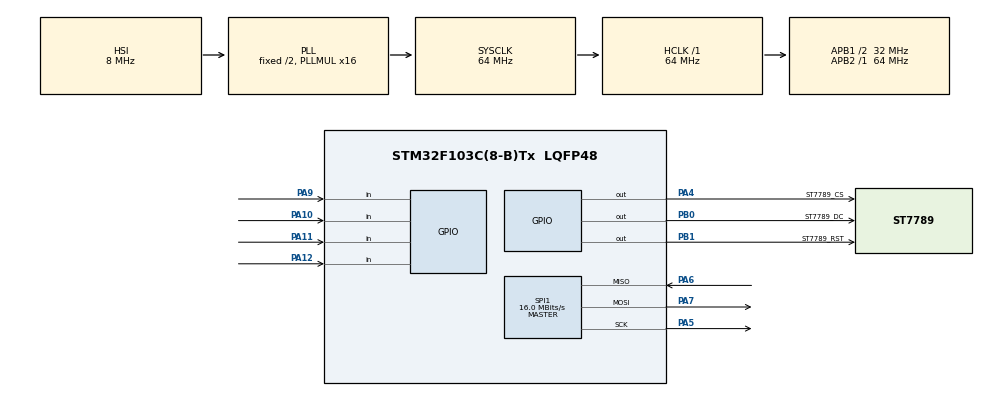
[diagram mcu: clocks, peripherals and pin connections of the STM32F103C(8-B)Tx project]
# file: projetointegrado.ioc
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Mcu.Family=STM32F1
Mcu.Name=STM32F103C(8-B)Tx
Mcu.Package=LQFP48
NVIC.PriorityGroup=NVIC_PRIORITYGROUP_4
PA10.GPIO_PuPd=GPIO_PULLUP
PA10.Signal=GPIO_Input
PA11.GPIO_PuPd=GPIO_PULLUP
PA11.Signal=GPIO_Input
PA12.GPIO_PuPd=GPIO_PULLUP
PA12.Signal=GPIO_Input
PA13.Mode=Serial_Wire
PA13.Signal=SYS_JTMS-SWDIO
PA14.Mode=Serial_Wire
PA14.Signal=SYS_JTCK-SWCLK
PA4.GPIO_Label=ST7789_CS
PA4.Signal=GPIO_Output
PA5.Mode=Full_Duplex_Master
PA5.Signal=SPI1_SCK
PA6.Mode=Full_Duplex_Master
PA6.Signal=SPI1_MISO
PA7.Mode=Full_Duplex_Master
PA7.Signal=SPI1_MOSI
PA9.GPIO_PuPd=GPIO_PULLUP
PA9.Signal=GPIO_Input
PB0.GPIO_Label=ST7789_DC
PB0.Signal=GPIO_Output
PB1.GPIO_Label=ST7789_RST
PB1.Signal=GPIO_Output
ProjectManager.HeapSize=0x200
ProjectManager.StackSize=0x400
ProjectManager.TargetToolchain=STM32CubeIDE
RCC.AHBFreq_Value=64000000
RCC.APB1CLKDivider=RCC_HCLK_DIV2
RCC.APB1Freq_Value=32000000
RCC.APB1TimFreq_Value=64000000
RCC.APB2Freq_Value=64000000
RCC.APB2TimFreq_Value=64000000
RCC.HCLKFreq_Value=64000000
RCC.PLLMUL=RCC_PLL_MUL16
RCC.SYSCLKFreq_VALUE=64000000
RCC.SYSCLKSource=RCC_SYSCLKSOURCE_PLLCLK
RCC.USBFreq_Value=64000000
SPI1.BaudRatePrescaler=SPI_BAUDRATEPRESCALER_4
SPI1.CLKPolarity=SPI_POLARITY_HIGH
SPI1.CalculateBaudRate=16.0 MBits/s
SPI1.Direction=SPI_DIRECTION_2LINES
SPI1.Mode=SPI_MODE_MASTER
SPI1.VirtualType=VM_MASTER
board=custom

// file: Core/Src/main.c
/* USER CODE BEGIN Header */
/**
  ******************************************************************************
  * @file           : main.c
  * @brief          : Main program body
  ******************************************************************************
  * @attention
  *
  * <h2><center>&copy; Copyright (c) 2025 STMicroelectronics.
  * All rights reserved.</center></h2>
  *
  * This software component is licensed by ST under BSD 3-Clause license,
  * the "License"; You may not use this file except in compliance with the
  * License. You may obtain a copy of the License at:
  *                        opensource.org/licenses/BSD-3-Clause
  *
  ******************************************************************************
  */
/* USER CODE END Header */
#include "main.h"
/* USER CODE BEGIN Includes */
#include "st7789\st7789.h"
#include <stdio.h>
#include <stdbool.h>
#include <stdlib.h>

/* USER CODE END Includes */

SPI_HandleTypeDef hspi1;

#define size 4
#define colorBG WHITE
#define colorCard BLACK
char tabuleiro[size][size];
int entradaCima = 0;
int entradaEsquerda = 0;
int entradaBaixo =0;
int entradaDireita =0;
int cursorX = 0;
int cursorY = 0;
int carta1X = 0;
int carta2X = 0;
int carta1Y = 0;
int carta2Y = 0;
int linha = 0;
int coluna = 0;
int verifica = 0;
bool revelado [size][size];
int selecionadas = 0;
int cor[size][size];
char cartas[size][size];
int tentativa = 0;
int tentativa2;
int recorde = 0;
char pt[15];
char rc[15];

#define CARTAPI_HEIGHT 30
#define CARTAPI_WIDTH 25

// array size is 2250
#define CARTAPI_HEIGHT 30
#define CARTAPI_WIDTH 25

// array size is 2250
#define CARTAPI_HEIGHT 30
#define CARTAPI_WIDTH 25

// array size is 1500
static const uint16_t cartaPI[][25*30/2]  = {
  0x0000, 0x0000, 0x0000, 0x0000, 0x0000, 0x0000, 0x0000, 0x0000, 0x0000, 0x0000, 0x0000, 0x0000, 0x0000, 0x0000, 0x0000, 0x0000, 0x0000, 0x0000, 0x0000, 0x0000, 0x0000, 0x0000, 0x0000, 0x0000, 0x0000,
  0x0000, 0xdd9e, 0xdd9e, 0xdd9e, 0xdd9e, 0xdd9e, 0xdd9e, 0xdd9e, 0xdd9e, 0xdd9e, 0xdd9e, 0xdd9e, 0xdd9e, 0xdd9e, 0xdd9e, 0xdd9e, 0xdd9e, 0xdd9e, 0xdd9e, 0xdd9e, 0xdd9e, 0xdd9e, 0xdd9e, 0xdd9e, 0x0000,
  0x0000, 0xdd9e, 0xffff, 0xffff, 0xffff, 0xffff, 0xffff, 0xffff, 0xffff, 0xffff, 0xffff, 0xffff, 0xffff, 0xffff, 0xffff, 0xffff, 0xffff, 0xffff, 0xffff, 0xffff, 0xffff, 0xffff, 0xffff, 0xdd9e, 0x0000,
  0x0000, 0xdd9e, 0xffff, 0xffff, 0xffff, 0xffff, 0xffff, 0xffff, 0xffff, 0xffff, 0xffff, 0xffff, 0xffff, 0xffff, 0xffff, 0xffff, 0xffff, 0xffff, 0xffff, 0xffff, 0xffff, 0xffff, 0xffff, 0xdd9e, 0x0000,
  0x0000, 0xdd9e, 0xffff, 0xffff, 0xdd9e, 0xdd9e, 0x1d05, 0xdd9e, 0xdd9e, 0x1d05, 0xdd9e, 0xdd9e, 0x1d05, 0xdd9e, 0xdd9e, 0x1d05, 0xdd9e, 0xdd9e, 0x1d05, 0xdd9e, 0xdd9e, 0xffff, 0xffff, 0xdd9e, 0x0000,
  0x0000, 0xdd9e, 0xffff, 0xffff, 0xdd9e, 0x1d05, 0xdd9e, 0x1d05, 0xdd9e, 0xdd9e, 0xdd9e, 0x1d05, 0xdd9e, 0x1d05, 0xdd9e, 0xdd9e, 0xdd9e, 0x1d05, 0xdd9e, 0x1d05, 0xdd9e, 0xffff, 0xffff, 0xdd9e, 0x0000,
  0x0000, 0xdd9e, 0xffff, 0xffff, 0x1d05, 0xdd9e, 0xdd9e, 0xdd9e, 0x1d05, 0xdd9e, 0x1d05, 0xdd9e, 0xdd9e, 0xdd9e, 0x1d05, 0xdd9e, 0x1d05, 0xdd9e, 0xdd9e, 0xdd9e, 0x1d05, 0xffff, 0xffff, 0xdd9e, 0x0000,
  0x0000, 0xdd9e, 0xffff, 0xffff, 0xdd9e, 0x1d05, 0xdd9e, 0x1d05, 0xdd9e, 0xdd9e, 0xdd9e, 0x1d05, 0xdd9e, 0x1d05, 0xdd9e, 0xdd9e, 0xdd9e, 0x1d05, 0xdd9e, 0x1d05, 0xdd9e, 0xffff, 0xffff, 0xdd9e, 0x0000,
  0x0000, 0xdd9e, 0xffff, 0xffff, 0xdd9e, 0xdd9e, 0x1d05, 0xdd9e, 0xdd9e, 0x1d05, 0xdd9e, 0xdd9e, 0x1d05, 0xdd9e, 0xdd9e, 0x1d05, 0xdd9e, 0xdd9e, 0x1d05, 0xdd9e, 0xdd9e, 0xffff, 0xffff, 0xdd9e, 0x0000,
  0x0000, 0xdd9e, 0xffff, 0xffff, 0xdd9e, 0x1d05, 0xdd9e, 0x1d05, 0xdd9e, 0xdd9e, 0xdd9e, 0x1d05, 0xdd9e, 0x1d05, 0xdd9e, 0xdd9e, 0xdd9e, 0x1d05, 0xdd9e, 0x1d05, 0xdd9e, 0xffff, 0xffff, 0xdd9e, 0x0000,
  0x0000, 0xdd9e, 0xffff, 0xffff, 0x1d05, 0xdd9e, 0xdd9e, 0xdd9e, 0x1d05, 0xdd9e, 0x1d05, 0xdd9e, 0xdd9e, 0xdd9e, 0x1d05, 0xdd9e, 0x1d05, 0xdd9e, 0xdd9e, 0xdd9e, 0x1d05, 0xffff, 0xffff, 0xdd9e, 0x0000,
  0x0000, 0xdd9e, 0xffff, 0xffff, 0xdd9e, 0x1d05, 0xdd9e, 0x1d05, 0xdd9e, 0xdd9e, 0xdd9e, 0x1d05, 0xdd9e, 0x1d05, 0xdd9e, 0xdd9e, 0xdd9e, 0x1d05, 0xdd9e, 0x1d05, 0xdd9e, 0xffff, 0xffff, 0xdd9e, 0x0000,
  0x0000, 0xdd9e, 0xffff, 0xffff, 0xdd9e, 0xdd9e, 0x1d05, 0xdd9e, 0xdd9e, 0x1d05, 0xdd9e, 0xdd9e, 0x1d05, 0xdd9e, 0xdd9e, 0x1d05, 0xdd9e, 0xdd9e, 0x1d05, 0xdd9e, 0xdd9e, 0xffff, 0xffff, 0xdd9e, 0x0000,
  0x0000, 0xdd9e, 0xffff, 0xffff, 0xdd9e, 0x1d05, 0xdd9e, 0x1d05, 0xdd9e, 0xdd9e, 0xdd9e, 0x1d05, 0xdd9e, 0x1d05, 0xdd9e, 0xdd9e, 0xdd9e, 0x1d05, 0xdd9e, 0x1d05, 0xdd9e, 0xffff, 0xffff, 0xdd9e, 0x0000,
  0x0000, 0xdd9e, 0xffff, 0xffff, 0x1d05, 0xdd9e, 0xdd9e, 0xdd9e, 0x1d05, 0xdd9e, 0x1d05, 0xdd9e, 0xdd9e, 0xdd9e, 0x1d05, 0xdd9e, 0x1d05, 0xdd9e, 0xdd9e, 0xdd9e, 0x1d05, 0xffff, 0xffff, 0xdd9e, 0x0000,
  0x0000, 0xdd9e, 0xffff, 0xffff, 0x1d05, 0xdd9e, 0xdd9e, 0xdd9e, 0x1d05, 0xdd9e, 0x1d05, 0xdd9e, 0xdd9e, 0xdd9e, 0x1d05, 0xdd9e, 0x1d05, 0xdd9e, 0xdd9e, 0xdd9e, 0x1d05, 0xffff, 0xffff, 0xdd9e, 0x0000,
  0x0000, 0xdd9e, 0xffff, 0xffff, 0xdd9e, 0x1d05, 0xdd9e, 0x1d05, 0xdd9e, 0xdd9e, 0xdd9e, 0x1d05, 0xdd9e, 0x1d05, 0xdd9e, 0xdd9e, 0xdd9e, 0x1d05, 0xdd9e, 0x1d05, 0xdd9e, 0xffff, 0xffff, 0xdd9e, 0x0000,
  0x0000, 0xdd9e, 0xffff, 0xffff, 0xdd9e, 0xdd9e, 0x1d05, 0xdd9e, 0xdd9e, 0x1d05, 0xdd9e, 0xdd9e, 0x1d05, 0xdd9e, 0xdd9e, 0x1d05, 0xdd9e, 0xdd9e, 0x1d05, 0xdd9e, 0xdd9e, 0xffff, 0xffff, 0xdd9e, 0x0000,
  0x0000, 0xdd9e, 0xffff, 0xffff, 0xdd9e, 0x1d05, 0xdd9e, 0x1d05, 0xdd9e, 0xdd9e, 0xdd9e, 0x1d05, 0xdd9e, 0x1d05, 0xdd9e, 0xdd9e, 0xdd9e, 0x1d05, 0xdd9e, 0x1d05, 0xdd9e, 0xffff, 0xffff, 0xdd9e, 0x0000,
  0x0000, 0xdd9e, 0xffff, 0xffff, 0x1d05, 0xdd9e, 0xdd9e, 0xdd9e, 0x1d05, 0xdd9e, 0x1d05, 0xdd9e, 0xdd9e, 0xdd9e, 0x1d05, 0xdd9e, 0x1d05, 0xdd9e, 0xdd9e, 0xdd9e, 0x1d05, 0xffff, 0xffff, 0xdd9e, 0x0000,
  0x0000, 0xdd9e, 0xffff, 0xffff, 0xdd9e, 0x1d05, 0xdd9e, 0x1d05, 0xdd9e, 0xdd9e, 0xdd9e, 0x1d05, 0xdd9e, 0x1d05, 0xdd9e, 0xdd9e, 0xdd9e, 0x1d05, 0xdd9e, 0x1d05, 0xdd9e, 0xffff, 0xffff, 0xdd9e, 0x0000,
  0x0000, 0xdd9e, 0xffff, 0xffff, 0xdd9e, 0xdd9e, 0x1d05, 0xdd9e, 0xdd9e, 0x1d05, 0xdd9e, 0xdd9e, 0x1d05, 0xdd9e, 0xdd9e, 0x1d05, 0xdd9e, 0xdd9e, 0x1d05, 0xdd9e, 0xdd9e, 0xffff, 0xffff, 0xdd9e, 0x0000,
  0x0000, 0xdd9e, 0xffff, 0xffff, 0xdd9e, 0x1d05, 0xdd9e, 0x1d05, 0xdd9e, 0xdd9e, 0xdd9e, 0x1d05, 0xdd9e, 0x1d05, 0xdd9e, 0xdd9e, 0xdd9e, 0x1d05, 0xdd9e, 0x1d05, 0xdd9e, 0xffff, 0xffff, 0xdd9e, 0x0000,
  0x0000, 0xdd9e, 0xffff, 0xffff, 0x1d05, 0xdd9e, 0xdd9e, 0xdd9e, 0x1d05, 0xdd9e, 0x1d05, 0xdd9e, 0xdd9e, 0xdd9e, 0x1d05, 0xdd9e, 0x1d05, 0xdd9e, 0xdd9e, 0xdd9e, 0x1d05, 0xffff, 0xffff, 0xdd9e, 0x0000,
  0x0000, 0xdd9e, 0xffff, 0xffff, 0xdd9e, 0x1d05, 0xdd9e, 0x1d05, 0xdd9e, 0xdd9e, 0xdd9e, 0x1d05, 0xdd9e, 0x1d05, 0xdd9e, 0xdd9e, 0xdd9e, 0x1d05, 0xdd9e, 0x1d05, 0xdd9e, 0xffff, 0xffff, 0xdd9e, 0x0000,
  0x0000, 0xdd9e, 0xffff, 0xffff, 0xdd9e, 0xdd9e, 0x1d05, 0xdd9e, 0xdd9e, 0x1d05, 0xdd9e, 0xdd9e, 0x1d05, 0xdd9e, 0xdd9e, 0x1d05, 0xdd9e, 0xdd9e, 0x1d05, 0xdd9e, 0xdd9e, 0xffff, 0xffff, 0xdd9e, 0x0000,
  0x0000, 0xdd9e, 0xffff, 0xffff, 0xffff, 0xffff, 0xffff, 0xffff, 0xffff, 0xffff, 0xffff, 0xffff, 0xffff, 0xffff, 0xffff, 0xffff, 0xffff, 0xffff, 0xffff, 0xffff, 0xffff, 0xffff, 0xffff, 0xdd9e, 0x0000,
  0x0000, 0xdd9e, 0xffff, 0xffff, 0xffff, 0xffff, 0xffff, 0xffff, 0xffff, 0xffff, 0xffff, 0xffff, 0xffff, 0xffff, 0xffff, 0xffff, 0xffff, 0xffff, 0xffff, 0xffff, 0xffff, 0xffff, 0xffff, 0xdd9e, 0x0000,
  0x0000, 0xdd9e, 0xdd9e, 0xdd9e, 0xdd9e, 0xdd9e, 0xdd9e, 0xdd9e, 0xdd9e, 0xdd9e, 0xdd9e, 0xdd9e, 0xdd9e, 0xdd9e, 0xdd9e, 0xdd9e, 0xdd9e, 0xdd9e, 0xdd9e, 0xdd9e, 0xdd9e, 0xdd9e, 0xdd9e, 0xdd9e, 0x0000,
  0x0000, 0x0000, 0x0000, 0x0000, 0x0000, 0x0000, 0x0000, 0x0000, 0x0000, 0x0000, 0x0000, 0x0000, 0x0000, 0x0000, 0x0000, 0x0000, 0x0000, 0x0000, 0x0000, 0x0000, 0x0000, 0x0000, 0x0000, 0x0000, 0x0000
};
#define NEW_PISKEL_1_PNG_HEIGHT 45
#define NEW_PISKEL_1_PNG_WIDTH 31

// array size is 2790
static const int16_t New_Piskel_1_png[][31*45/2]  = {
  0x0000, 0x0000, 0x0000, 0x0000, 0x0000, 0x0000, 0x0000, 0x0000, 0x0000, 0x0000, 0x0000, 0x0000, 0x0000, 0x0000, 0x0000, 0x0000, 0x0000, 0x0000, 0x0000, 0x0000, 0x0000, 0x0000, 0x0000, 0x0000, 0x0000, 0x0000, 0x0000, 0x0000, 0x0000, 0x0000, 0x0000,
  0x0000, 0x5f7c, 0x5f7c, 0x5f7c, 0x5f7c, 0x5f7c, 0x5f7c, 0x5f7c, 0x5f7c, 0x5f7c, 0x5f7c, 0x5f7c, 0x5f7c, 0x5f7c, 0x5f7c, 0x5f7c, 0x5f7c, 0x5f7c, 0x5f7c, 0x5f7c, 0x5f7c, 0x5f7c, 0x5f7c, 0x5f7c, 0x5f7c, 0x5f7c, 0x5f7c, 0x5f7c, 0x5f7c, 0x5f7c, 0x0000,
  0x0000, 0x5f7c, 0xffde, 0xffde, 0xffde, 0xffde, 0xffde, 0xffde, 0xffde, 0xffde, 0xffde, 0xffde, 0xffde, 0xffde, 0xffde, 0xffde, 0xffde, 0xffde, 0xffde, 0xffde, 0xffde, 0xffde, 0xffde, 0xffde, 0xffde, 0xffde, 0xffde, 0xffde, 0xffde, 0x5f7c, 0x0000,
  0x0000, 0x5f7c, 0xffde, 0xffde, 0xffde, 0xffde, 0xffde, 0xffde, 0xffde, 0xffde, 0xffde, 0xffde, 0xffde, 0xffde, 0xffde, 0xffde, 0xffde, 0xffde, 0xffde, 0xffde, 0xffde, 0xffde, 0xffde, 0xffde, 0xffde, 0xffde, 0xffde, 0xffde, 0xffde, 0x5f7c, 0x0000,
  0x0000, 0x5f7c, 0xffde, 0xffde, 0x5f7c, 0x5f7c, 0x5f7c, 0xdf21, 0x5f7c, 0x5f7c, 0x5f7c, 0x5f7c, 0x5f7c, 0x5f7c, 0x5f7c, 0xdf21, 0x5f7c, 0x5f7c, 0x5f7c, 0x5f7c, 0x5f7c, 0x5f7c, 0x5f7c, 0xdf21, 0x5f7c, 0x5f7c, 0x5f7c, 0xffde, 0xffde, 0x5f7c, 0x0000,
  0x0000, 0x5f7c, 0xffde, 0xffde, 0x5f7c, 0x5f7c, 0xdf21, 0x5f7c, 0xdf21, 0x5f7c, 0x5f7c, 0x5f7c, 0x5f7c, 0x5f7c, 0xdf21, 0x5f7c, 0xdf21, 0x5f7c, 0x5f7c, 0x5f7c, 0x5f7c, 0x5f7c, 0xdf21, 0x5f7c, 0xdf21, 0x5f7c, 0x5f7c, 0xffde, 0xffde, 0x5f7c, 0x0000,
  0x0000, 0x5f7c, 0xffde, 0xffde, 0x5f7c, 0xdf21, 0x5f7c, 0x5f7c, 0x5f7c, 0xdf21, 0x5f7c, 0x5f7c, 0x5f7c, 0xdf21, 0x5f7c, 0x5f7c, 0x5f7c, 0xdf21, 0x5f7c, 0x5f7c, 0x5f7c, 0xdf21, 0x5f7c, 0x5f7c, 0x5f7c, 0xdf21, 0x5f7c, 0xffde, 0xffde, 0x5f7c, 0x0000,
  0x0000, 0x5f7c, 0xffde, 0xffde, 0xdf21, 0x5f7c, 0x5f7c, 0x5f7c, 0x5f7c, 0x5f7c, 0xdf21, 0x5f7c, 0xdf21, 0x5f7c, 0x5f7c, 0x5f7c, 0x5f7c, 0x5f7c, 0xdf21, 0x5f7c, 0xdf21, 0x5f7c, 0x5f7c, 0x5f7c, 0x5f7c, 0x5f7c, 0xdf21, 0xffde, 0xffde, 0x5f7c, 0x0000,
  0x0000, 0x5f7c, 0xffde, 0xffde, 0x5f7c, 0xdf21, 0x5f7c, 0x5f7c, 0x5f7c, 0xdf21, 0x5f7c, 0x5f7c, 0x5f7c, 0xdf21, 0x5f7c, 0x5f7c, 0x5f7c, 0xdf21, 0x5f7c, 0x5f7c, 0x5f7c, 0xdf21, 0x5f7c, 0x5f7c, 0x5f7c, 0xdf21, 0x5f7c, 0xffde, 0xffde, 0x5f7c, 0x0000,
  0x0000, 0x5f7c, 0xffde, 0xffde, 0x5f7c, 0x5f7c, 0xdf21, 0x5f7c, 0xdf21, 0x5f7c, 0x5f7c, 0x5f7c, 0x5f7c, 0x5f7c, 0xdf21, 0x5f7c, 0xdf21, 0x5f7c, 0x5f7c, 0x5f7c, 0x5f7c, 0x5f7c, 0xdf21, 0x5f7c, 0xdf21, 0x5f7c, 0x5f7c, 0xffde, 0xffde, 0x5f7c, 0x0000,
  0x0000, 0x5f7c, 0xffde, 0xffde, 0x5f7c, 0x5f7c, 0x5f7c, 0xdf21, 0x5f7c, 0x5f7c, 0x5f7c, 0x5f7c, 0x5f7c, 0x5f7c, 0x5f7c, 0xdf21, 0x5f7c, 0x5f7c, 0x5f7c, 0x5f7c, 0x5f7c, 0x5f7c, 0x5f7c, 0xdf21, 0x5f7c, 0x5f7c, 0x5f7c, 0xffde, 0xffde, 0x5f7c, 0x0000,
  0x0000, 0x5f7c, 0xffde, 0xffde, 0x5f7c, 0x5f7c, 0xdf21, 0x5f7c, 0xdf21, 0x5f7c, 0x5f7c, 0x5f7c, 0x5f7c, 0x5f7c, 0xdf21, 0x5f7c, 0xdf21, 0x5f7c, 0x5f7c, 0x5f7c, 0x5f7c, 0x5f7c, 0xdf21, 0x5f7c, 0xdf21, 0x5f7c, 0x5f7c, 0xffde, 0xffde, 0x5f7c, 0x0000,
  0x0000, 0x5f7c, 0xffde, 0xffde, 0x5f7c, 0xdf21, 0x5f7c, 0x5f7c, 0x5f7c, 0xdf21, 0x5f7c, 0x5f7c, 0x5f7c, 0xdf21, 0x5f7c, 0x5f7c, 0x5f7c, 0xdf21, 0x5f7c, 0x5f7c, 0x5f7c, 0xdf21, 0x5f7c, 0x5f7c, 0x5f7c, 0xdf21, 0x5f7c, 0xffde, 0xffde, 0x5f7c, 0x0000,
  0x0000, 0x5f7c, 0xffde, 0xffde, 0xdf21, 0x5f7c, 0x5f7c, 0x5f7c, 0x5f7c, 0x5f7c, 0xdf21, 0x5f7c, 0xdf21, 0x5f7c, 0x5f7c, 0x5f7c, 0x5f7c, 0x5f7c, 0xdf21, 0x5f7c, 0xdf21, 0x5f7c, 0x5f7c, 0x5f7c, 0x5f7c, 0x5f7c, 0xdf21, 0xffde, 0xffde, 0x5f7c, 0x0000,
  0x0000, 0x5f7c, 0xffde, 0xffde, 0x5f7c, 0xdf21, 0x5f7c, 0x5f7c, 0x5f7c, 0xdf21, 0x5f7c, 0x5f7c, 0x5f7c, 0xdf21, 0x5f7c, 0x5f7c, 0x5f7c, 0xdf21, 0x5f7c, 0x5f7c, 0x5f7c, 0xdf21, 0x5f7c, 0x5f7c, 0x5f7c, 0xdf21, 0x5f7c, 0xffde, 0xffde, 0x5f7c, 0x0000,
  0x0000, 0x5f7c, 0xffde, 0xffde, 0x5f7c, 0x5f7c, 0xdf21, 0x5f7c, 0xdf21, 0x5f7c, 0x5f7c, 0x5f7c, 0x5f7c, 0x5f7c, 0xdf21, 0x5f7c, 0xdf21, 0x5f7c, 0x5f7c, 0x5f7c, 0x5f7c, 0x5f7c, 0xdf21, 0x5f7c, 0xdf21, 0x5f7c, 0x5f7c, 0xffde, 0xffde, 0x5f7c, 0x0000,
  0x0000, 0x5f7c, 0xffde, 0xffde, 0x5f7c, 0x5f7c, 0x5f7c, 0xdf21, 0x5f7c, 0x5f7c, 0x5f7c, 0x5f7c, 0x5f7c, 0x5f7c, 0x5f7c, 0xdf21, 0x5f7c, 0x5f7c, 0x5f7c, 0x5f7c, 0x5f7c, 0x5f7c, 0x5f7c, 0xdf21, 0x5f7c, 0x5f7c, 0x5f7c, 0xffde, 0xffde, 0x5f7c, 0x0000,
  0x0000, 0x5f7c, 0xffde, 0xffde, 0x5f7c, 0x5f7c, 0xdf21, 0x5f7c, 0xdf21, 0x5f7c, 0x5f7c, 0x5f7c, 0x5f7c, 0x5f7c, 0xdf21, 0x5f7c, 0xdf21, 0x5f7c, 0x5f7c, 0x5f7c, 0x5f7c, 0x5f7c, 0xdf21, 0x5f7c, 0xdf21, 0x5f7c, 0x5f7c, 0xffde, 0xffde, 0x5f7c, 0x0000,
  0x0000, 0x5f7c, 0xffde, 0xffde, 0x5f7c, 0xdf21, 0x5f7c, 0x5f7c, 0x5f7c, 0xdf21, 0x5f7c, 0x5f7c, 0x5f7c, 0xdf21, 0x5f7c, 0x5f7c, 0x5f7c, 0xdf21, 0x5f7c, 0x5f7c, 0x5f7c, 0xdf21, 0x5f7c, 0x5f7c, 0x5f7c, 0xdf21, 0x5f7c, 0xffde, 0xffde, 0x5f7c, 0x0000,
  0x0000, 0x5f7c, 0xffde, 0xffde, 0xdf21, 0x5f7c, 0x5f7c, 0x5f7c, 0x5f7c, 0x5f7c, 0xdf21, 0x5f7c, 0xdf21, 0x5f7c, 0x5f7c, 0x5f7c, 0x5f7c, 0x5f7c, 0xdf21, 0x5f7c, 0xdf21, 0x5f7c, 0x5f7c, 0x5f7c, 0x5f7c, 0x5f7c, 0xdf21, 0xffde, 0xffde, 0x5f7c, 0x0000,
  0x0000, 0x5f7c, 0xffde, 0xffde, 0x5f7c, 0xdf21, 0x5f7c, 0x5f7c, 0x5f7c, 0xdf21, 0x5f7c, 0x5f7c, 0x5f7c, 0xdf21, 0x5f7c, 0x5f7c, 0x5f7c, 0xdf21, 0x5f7c, 0x5f7c, 0x5f7c, 0xdf21, 0x5f7c, 0x5f7c, 0x5f7c, 0xdf21, 0x5f7c, 0xffde, 0xffde, 0x5f7c, 0x0000,
  0x0000, 0x5f7c, 0xffde, 0xffde, 0x5f7c, 0x5f7c, 0xdf21, 0x5f7c, 0xdf21, 0x5f7c, 0x5f7c, 0x5f7c, 0x5f7c, 0x5f7c, 0xdf21, 0x5f7c, 0xdf21, 0x5f7c, 0x5f7c, 0x5f7c, 0x5f7c, 0x5f7c, 0xdf21, 0x5f7c, 0xdf21, 0x5f7c, 0x5f7c, 0xffde, 0xffde, 0x5f7c, 0x0000,
  0x0000, 0x5f7c, 0xffde, 0xffde, 0x5f7c, 0x5f7c, 0x5f7c, 0xdf21, 0x5f7c, 0x5f7c, 0x5f7c, 0x5f7c, 0x5f7c, 0x5f7c, 0x5f7c, 0xdf21, 0x5f7c, 0x5f7c, 0x5f7c, 0x5f7c, 0x5f7c, 0x5f7c, 0x5f7c, 0xdf21, 0x5f7c, 0x5f7c, 0x5f7c, 0xffde, 0xffde, 0x5f7c, 0x0000,
  0x0000, 0x5f7c, 0xffde, 0xffde, 0x5f7c, 0x5f7c, 0xdf21, 0x5f7c, 0xdf21, 0x5f7c, 0x5f7c, 0x5f7c, 0x5f7c, 0x5f7c, 0xdf21, 0x5f7c, 0xdf21, 0x5f7c, 0x5f7c, 0x5f7c, 0x5f7c, 0x5f7c, 0xdf21, 0x5f7c, 0xdf21, 0x5f7c, 0x5f7c, 0xffde, 0xffde, 0x5f7c, 0x0000,
  0x0000, 0x5f7c, 0xffde, 0xffde, 0x5f7c, 0xdf21, 0x5f7c, 0x5f7c, 0x5f7c, 0xdf21, 0x5f7c, 0x5f7c, 0x5f7c, 0xdf21, 0x5f7c, 0x5f7c, 0x5f7c, 0xdf21, 0x5f7c, 0x5f7c, 0x5f7c, 0xdf21, 0x5f7c, 0x5f7c, 0x5f7c, 0xdf21, 0x5f7c, 0xffde, 0xffde, 0x5f7c, 0x0000,
  0x0000, 0x5f7c, 0xffde, 0xffde, 0xdf21, 0x5f7c, 0x5f7c, 0x5f7c, 0x5f7c, 0x5f7c, 0xdf21, 0x5f7c, 0xdf21, 0x5f7c, 0x5f7c, 0x5f7c, 0x5f7c, 0x5f7c, 0xdf21, 0x5f7c, 0xdf21, 0x5f7c, 0x5f7c, 0x5f7c, 0x5f7c, 0x5f7c, 0xdf21, 0xffde, 0xffde, 0x5f7c, 0x0000,
  0x0000, 0x5f7c, 0xffde, 0xffde, 0x5f7c, 0xdf21, 0x5f7c, 0x5f7c, 0x5f7c, 0xdf21, 0x5f7c, 0x5f7c, 0x5f7c, 0xdf21, 0x5f7c, 0x5f7c, 0x5f7c, 0xdf21, 0x5f7c, 0x5f7c, 0x5f7c, 0xdf21, 0x5f7c, 0x5f7c, 0x5f7c, 0xdf21, 0x5f7c, 0xffde, 0xffde, 0x5f7c, 0x0000,
  0x0000, 0x5f7c, 0xffde, 0xffde, 0x5f7c, 0x5f7c, 0xdf21, 0x5f7c, 0xdf21, 0x5f7c, 0x5f7c, 0x5f7c, 0x5f7c, 0x5f7c, 0xdf21, 0x5f7c, 0xdf21, 0x5f7c, 0x5f7c, 0x5f7c, 0x5f7c, 0x5f7c, 0xdf21, 0x5f7c, 0xdf21, 0x5f7c, 0x5f7c, 0xffde, 0xffde, 0x5f7c, 0x0000,
  0x0000, 0x5f7c, 0xffde, 0xffde, 0x5f7c, 0x5f7c, 0x5f7c, 0xdf21, 0x5f7c, 0x5f7c, 0x5f7c, 0x5f7c, 0x5f7c, 0x5f7c, 0x5f7c, 0xdf21, 0x5f7c, 0x5f7c, 0x5f7c, 0x5f7c, 0x5f7c, 0x5f7c, 0x5f7c, 0xdf21, 0x5f7c, 0x5f7c, 0x5f7c, 0xffde, 0xffde, 0x5f7c, 0x0000,
  0x0000, 0x5f7c, 0xffde, 0xffde, 0x5f7c, 0x5f7c, 0xdf21, 0x5f7c, 0xdf21, 0x5f7c, 0x5f7c, 0x5f7c, 0x5f7c, 0x5f7c, 0xdf21, 0x5f7c, 0xdf21, 0x5f7c, 0x5f7c, 0x5f7c, 0x5f7c, 0x5f7c, 0xdf21, 0x5f7c, 0xdf21, 0x5f7c, 0x5f7c, 0xffde, 0xffde, 0x5f7c, 0x0000,
  0x0000, 0x5f7c, 0xffde, 0xffde, 0x5f7c, 0xdf21, 0x5f7c, 0x5f7c, 0x5f7c, 0xdf21, 0x5f7c, 0x5f7c, 0x5f7c, 0xdf21, 0x5f7c, 0x5f7c, 0x5f7c, 0xdf21, 0x5f7c, 0x5f7c, 0x5f7c, 0xdf21, 0x5f7c, 0x5f7c, 0x5f7c, 0xdf21, 0x5f7c, 0xffde, 0xffde, 0x5f7c, 0x0000,
  0x0000, 0x5f7c, 0xffde, 0xffde, 0xdf21, 0x5f7c, 0x5f7c, 0x5f7c, 0x5f7c, 0x5f7c, 0xdf21, 0x5f7c, 0xdf21, 0x5f7c, 0x5f7c, 0x5f7c, 0x5f7c, 0x5f7c, 0xdf21, 0x5f7c, 0xdf21, 0x5f7c, 0x5f7c, 0x5f7c, 0x5f7c, 0x5f7c, 0xdf21, 0xffde, 0xffde, 0x5f7c, 0x0000,
  0x0000, 0x5f7c, 0xffde, 0xffde, 0x5f7c, 0xdf21, 0x5f7c, 0x5f7c, 0x5f7c, 0xdf21, 0x5f7c, 0x5f7c, 0x5f7c, 0xdf21, 0x5f7c, 0x5f7c, 0x5f7c, 0xdf21, 0x5f7c, 0x5f7c, 0x5f7c, 0xdf21, 0x5f7c, 0x5f7c, 0x5f7c, 0xdf21, 0x5f7c, 0xffde, 0xffde, 0x5f7c, 0x0000,
  0x0000, 0x5f7c, 0xffde, 0xffde, 0x5f7c, 0x5f7c, 0xdf21, 0x5f7c, 0xdf21, 0x5f7c, 0x5f7c, 0x5f7c, 0x5f7c, 0x5f7c, 0xdf21, 0x5f7c, 0xdf21, 0x5f7c, 0x5f7c, 0x5f7c, 0x5f7c, 0x5f7c, 0xdf21, 0x5f7c, 0xdf21, 0x5f7c, 0x5f7c, 0xffde, 0xffde, 0x5f7c, 0x0000,
  0x0000, 0x5f7c, 0xffde, 0xffde, 0x5f7c, 0x5f7c, 0x5f7c, 0xdf21, 0x5f7c, 0x5f7c, 0x5f7c, 0x5f7c, 0x5f7c, 0x5f7c, 0x5f7c, 0xdf21, 0x5f7c, 0x5f7c, 0x5f7c, 0x5f7c, 0x5f7c, 0x5f7c, 0x5f7c, 0xdf21, 0x5f7c, 0x5f7c, 0x5f7c, 0xffde, 0xffde, 0x5f7c, 0x0000,
  0x0000, 0x5f7c, 0xffde, 0xffde, 0x5f7c, 0x5f7c, 0xdf21, 0x5f7c, 0xdf21, 0x5f7c, 0x5f7c, 0x5f7c, 0x5f7c, 0x5f7c, 0xdf21, 0x5f7c, 0xdf21, 0x5f7c, 0x5f7c, 0x5f7c, 0x5f7c, 0x5f7c, 0xdf21, 0x5f7c, 0xdf21, 0x5f7c, 0x5f7c, 0xffde, 0xffde, 0x5f7c, 0x0000,
  0x0000, 0x5f7c, 0xffde, 0xffde, 0x5f7c, 0xdf21, 0x5f7c, 0x5f7c, 0x5f7c, 0xdf21, 0x5f7c, 0x5f7c, 0x5f7c, 0xdf21, 0x5f7c, 0x5f7c, 0x5f7c, 0xdf21, 0x5f7c, 0x5f7c, 0x5f7c, 0xdf21, 0x5f7c, 0x5f7c, 0x5f7c, 0xdf21, 0x5f7c, 0xffde, 0xffde, 0x5f7c, 0x0000,
  0x0000, 0x5f7c, 0xffde, 0xffde, 0xdf21, 0x5f7c, 0x5f7c, 0x5f7c, 0x5f7c, 0x5f7c, 0xdf21, 0x5f7c, 0xdf21, 0x5f7c, 0x5f7c, 0x5f7c, 0x5f7c, 0x5f7c, 0xdf21, 0x5f7c, 0xdf21, 0x5f7c, 0x5f7c, 0x5f7c, 0x5f7c, 0x5f7c, 0xdf21, 0xffde, 0xffde, 0x5f7c, 0x0000,
  0x0000, 0x5f7c, 0xffde, 0xffde, 0x5f7c, 0xdf21, 0x5f7c, 0x5f7c, 0x5f7c, 0xdf21, 0x5f7c, 0x5f7c, 0x5f7c, 0xdf21, 0x5f7c, 0x5f7c, 0x5f7c, 0xdf21, 0x5f7c, 0x5f7c, 0x5f7c, 0xdf21, 0x5f7c, 0x5f7c, 0x5f7c, 0xdf21, 0x5f7c, 0xffde, 0xffde, 0x5f7c, 0x0000,
  0x0000, 0x5f7c, 0xffde, 0xffde, 0x5f7c, 0x5f7c, 0xdf21, 0x5f7c, 0xdf21, 0x5f7c, 0x5f7c, 0x5f7c, 0x5f7c, 0x5f7c, 0xdf21, 0x5f7c, 0xdf21, 0x5f7c, 0x5f7c, 0x5f7c, 0x5f7c, 0x5f7c, 0xdf21, 0x5f7c, 0xdf21, 0x5f7c, 0x5f7c, 0xffde, 0xffde, 0x5f7c, 0x0000,
  0x0000, 0x5f7c, 0xffde, 0xffde, 0x5f7c, 0x5f7c, 0x5f7c, 0xdf21, 0x5f7c, 0x5f7c, 0x5f7c, 0x5f7c, 0x5f7c, 0x5f7c, 0x5f7c, 0xdf21, 0x5f7c, 0x5f7c, 0x5f7c, 0x5f7c, 0x5f7c, 0x5f7c, 0x5f7c, 0xdf21, 0x5f7c, 0x5f7c, 0x5f7c, 0xffde, 0xffde, 0x5f7c, 0x0000,
  0x0000, 0x5f7c, 0xffde, 0xffde, 0xffde, 0xffde, 0xffde, 0xffde, 0xffde, 0xffde, 0xffde, 0xffde, 0xffde, 0xffde, 0xffde, 0xffde, 0xffde, 0xffde, 0xffde, 0xffde, 0xffde, 0xffde, 0xffde, 0xffde, 0xffde, 0xffde, 0xffde, 0xffde, 0xffde, 0x5f7c, 0x0000,
  0x0000, 0x5f7c, 0xffde, 0xffde, 0xffde, 0xffde, 0xffde, 0xffde, 0xffde, 0xffde, 0xffde, 0xffde, 0xffde, 0xffde, 0xffde, 0xffde, 0xffde, 0xffde, 0xffde, 0xffde, 0xffde, 0xffde, 0xffde, 0xffde, 0xffde, 0xffde, 0xffde, 0xffde, 0xffde, 0x5f7c, 0x0000,
  0x0000, 0x5f7c, 0x5f7c, 0x5f7c, 0x5f7c, 0x5f7c, 0x5f7c, 0x5f7c, 0x5f7c, 0x5f7c, 0x5f7c, 0x5f7c, 0x5f7c, 0x5f7c, 0x5f7c, 0x5f7c, 0x5f7c, 0x5f7c, 0x5f7c, 0x5f7c, 0x5f7c, 0x5f7c, 0x5f7c, 0x5f7c, 0x5f7c, 0x5f7c, 0x5f7c, 0x5f7c, 0x5f7c, 0x5f7c, 0x0000,
  0x0000, 0x0000, 0x0000, 0x0000, 0x0000, 0x0000, 0x0000, 0x0000, 0x0000, 0x0000, 0x0000, 0x0000, 0x0000, 0x0000, 0x0000, 0x0000, 0x0000, 0x0000, 0x0000, 0x0000, 0x0000, 0x0000, 0x0000, 0x0000, 0x0000, 0x0000, 0x0000, 0x0000, 0x0000, 0x0000, 0x0000
};
void SystemClock_Config(void);
static void MX_GPIO_Init(void);
static void MX_SPI1_Init(void);
/* USER CODE BEGIN PFP */
void gerarPares(char tabuleiro[size][size]);
void IniciarJogo(char tabuleiro[size][size]);
void navegarCursor(int *cursorX , int *cursorY);
void selecionarCartas(bool revelado[size][size], int *cursorX, int *cursorY, int* cartaX, int* cartaY);
void desenharTabuleiro();
bool comparar(int carta1X, int carta1Y, int carta2X, int carta2Y);
void verificaVitoria();
void tentativaf();
void atualizarecorde();
void fimdeJogo();
void menu();

/* USER CODE END PFP */

int main(void)
{

  /* MCU Configuration--------------------------------------------------------*/

  /* Reset of all peripherals, Initializes the Flash interface and the Systick. */
  HAL_Init();

  /* Configure the system clock */
  SystemClock_Config();

  /* Initialize all configured peripherals */
  MX_GPIO_Init();
  MX_SPI1_Init();
  /* USER CODE BEGIN 2 */
  ST7789_Init();
  /* USER CODE END 2 */

  /* Infinite loop */
  while (1)
  {
	  srand(time(NULL));
	  	  menu();
	  	  ST7789_Fill_Color(colorCard);
	  	  IniciarJogo(tabuleiro);

	  	  ST7789_Fill_Color(colorCard);

	  	  ST7789_DrawImage(30, 30, 25, 30, cartaPI);
	  	  ST7789_DrawImage(30, 80, 25, 30, cartaPI);
	  	  ST7789_DrawImage(30, 130, 25, 30, cartaPI);
	  	  ST7789_DrawImage(30, 180, 25, 30, cartaPI);

	  	  ST7789_DrawImage(85, 30, 25, 30, cartaPI);
	  	  ST7789_DrawImage(85, 80, 25, 30, cartaPI);
	  	  ST7789_DrawImage(85, 130, 25, 30, cartaPI);
	  	  ST7789_DrawImage(85, 180, 25, 30, cartaPI);

	  	  ST7789_DrawImage(140, 30, 25, 30, cartaPI);
	  	  ST7789_DrawImage(140, 80, 25, 30, cartaPI);
	  	  ST7789_DrawImage(140, 130, 25, 30, cartaPI);
	  	  ST7789_DrawImage(140, 180, 25, 30, cartaPI);

	  	  ST7789_DrawImage(195, 30, 25, 30, cartaPI);
	  	  ST7789_DrawImage(195, 80, 25, 30, cartaPI);
	  	  ST7789_DrawImage(195, 130, 25, 30, cartaPI);
	  	  ST7789_DrawImage(195, 180, 25, 30, cartaPI);
	  	  while(verifica == 1){
	  		  navegarCursor(&cursorX,&cursorY);
	  		  //desenharTabuleiro();
	  		  if (entradaBaixo == 0) {
	  	          selecionarCartas(revelado, &cursorX, &cursorY, &carta1X, &carta1Y);
	  	          verificaVitoria();
	  	      }
	  	  }

  }
}

void SystemClock_Config(void)
{
  RCC_OscInitTypeDef RCC_OscInitStruct = {0};
  RCC_ClkInitTypeDef RCC_ClkInitStruct = {0};

  /** Initializes the RCC Oscillators according to the specified parameters
  * in the RCC_OscInitTypeDef structure.
  */
  RCC_OscInitStruct.OscillatorType = RCC_OSCILLATORTYPE_HSI;
  RCC_OscInitStruct.HSIState = RCC_HSI_ON;
  RCC_OscInitStruct.HSICalibrationValue = RCC_HSICALIBRATION_DEFAULT;
  RCC_OscInitStruct.PLL.PLLState = RCC_PLL_ON;
  RCC_OscInitStruct.PLL.PLLSource = RCC_PLLSOURCE_HSI_DIV2;
  RCC_OscInitStruct.PLL.PLLMUL = RCC_PLL_MUL16;
  if (HAL_RCC_OscConfig(&RCC_OscInitStruct) != HAL_OK)
  {
    Error_Handler();
  }
  /** Initializes the CPU, AHB and APB buses clocks
  */
  RCC_ClkInitStruct.ClockType = RCC_CLOCKTYPE_HCLK|RCC_CLOCKTYPE_SYSCLK
                              |RCC_CLOCKTYPE_PCLK1|RCC_CLOCKTYPE_PCLK2;
  RCC_ClkInitStruct.SYSCLKSource = RCC_SYSCLKSOURCE_PLLCLK;
  RCC_ClkInitStruct.AHBCLKDivider = RCC_SYSCLK_DIV1;
  RCC_ClkInitStruct.APB1CLKDivider = RCC_HCLK_DIV2;
  RCC_ClkInitStruct.APB2CLKDivider = RCC_HCLK_DIV1;

  if (HAL_RCC_ClockConfig(&RCC_ClkInitStruct, FLASH_LATENCY_2) != HAL_OK)
  {
    Error_Handler();
  }
}

static void MX_SPI1_Init(void)
{

  /* SPI1 parameter configuration*/
  hspi1.Instance = SPI1;
  hspi1.Init.Mode = SPI_MODE_MASTER;
  hspi1.Init.Direction = SPI_DIRECTION_2LINES;
  hspi1.Init.DataSize = SPI_DATASIZE_8BIT;
  hspi1.Init.CLKPolarity = SPI_POLARITY_HIGH;
  hspi1.Init.CLKPhase = SPI_PHASE_1EDGE;
  hspi1.Init.NSS = SPI_NSS_SOFT;
  hspi1.Init.BaudRatePrescaler = SPI_BAUDRATEPRESCALER_4;
  hspi1.Init.FirstBit = SPI_FIRSTBIT_MSB;
  hspi1.Init.TIMode = SPI_TIMODE_DISABLE;
  hspi1.Init.CRCCalculation = SPI_CRCCALCULATION_DISABLE;
  hspi1.Init.CRCPolynomial = 10;
  if (HAL_SPI_Init(&hspi1) != HAL_OK)
  {
    Error_Handler();
  }

}

static void MX_GPIO_Init(void)
{
  GPIO_InitTypeDef GPIO_InitStruct = {0};

  /* GPIO Ports Clock Enable */
  __HAL_RCC_GPIOA_CLK_ENABLE();
  __HAL_RCC_GPIOB_CLK_ENABLE();

  /*Configure GPIO pin Output Level */
  HAL_GPIO_WritePin(ST7789_CS_GPIO_Port, ST7789_CS_Pin, GPIO_PIN_RESET);

  /*Configure GPIO pin Output Level */
  HAL_GPIO_WritePin(GPIOB, ST7789_DC_Pin|ST7789_RST_Pin|GPIO_PIN_3|GPIO_PIN_4
                          |GPIO_PIN_5|GPIO_PIN_6, GPIO_PIN_RESET);

  /*Configure GPIO pin : ST7789_CS_Pin */
  GPIO_InitStruct.Pin = ST7789_CS_Pin;
  GPIO_InitStruct.Mode = GPIO_MODE_OUTPUT_PP;
  GPIO_InitStruct.Pull = GPIO_NOPULL;
  GPIO_InitStruct.Speed = GPIO_SPEED_FREQ_LOW;
  HAL_GPIO_Init(ST7789_CS_GPIO_Port, &GPIO_InitStruct);

  /*Configure GPIO pins : ST7789_DC_Pin ST7789_RST_Pin PB3 PB4
                           PB5 PB6 */
  GPIO_InitStruct.Pin = ST7789_DC_Pin|ST7789_RST_Pin|GPIO_PIN_3|GPIO_PIN_4
                          |GPIO_PIN_5|GPIO_PIN_6;
  GPIO_InitStruct.Mode = GPIO_MODE_OUTPUT_PP;
  GPIO_InitStruct.Pull = GPIO_NOPULL;
  GPIO_InitStruct.Speed = GPIO_SPEED_FREQ_LOW;
  HAL_GPIO_Init(GPIOB, &GPIO_InitStruct);

  /*Configure GPIO pins : PA9 PA10 PA11 PA12 */
  GPIO_InitStruct.Pin = GPIO_PIN_9|GPIO_PIN_10|GPIO_PIN_11|GPIO_PIN_12;
  GPIO_InitStruct.Mode = GPIO_MODE_INPUT;
  GPIO_InitStruct.Pull = GPIO_PULLDOWN;
  HAL_GPIO_Init(GPIOA, &GPIO_InitStruct);

}

/* USER CODE BEGIN 4 */
void tentativaf(){
	tentativa ++;
	sprintf(pt, "Tentativa: %d", tentativa);
	ST7789_WriteString(63,4, pt ,Font_11x18, WHITE, colorCard );

}

void atualizarecorde(){
	if(recorde == 0){
		recorde = tentativa;
	}
	else if(tentativa < recorde){ //primeiro jogo
		recorde = tentativa;
	}

	sprintf(rc, "Recorde %d", recorde);
	ST7789_WriteString(68,175, rc ,Font_11x18, YELLOW, colorCard );
}

void verificaVitoria() {
	int contador1 = 0;
    for (int linha = 0; linha < size; linha++) {
        for (int coluna = 0; coluna < size; coluna++) {
            if (revelado[linha][coluna])
            {
            	contador1++;
            }
        }
    }
    if(contador1 == 16)
    {
    	atualizarecorde();
    	verifica = 0;
    	fimdeJogo();
    	HAL_Delay(7000);

    }
}
void navegarCursor(int *cursorX,int *cursorY){//talvez colocar todos os cursores como ponteiro para alterar o valor para todas as funções
	entradaCima = HAL_GPIO_ReadPin(GPIOA, GPIO_PIN_12);
	entradaDireita = HAL_GPIO_ReadPin(GPIOA, GPIO_PIN_11);
	entradaBaixo = HAL_GPIO_ReadPin(GPIOA, GPIO_PIN_10);
	entradaEsquerda = HAL_GPIO_ReadPin(GPIOA, GPIO_PIN_9);
	static int cursorX_antigo = 0;
	static int cursorY_antigo = 0;

				if (entradaCima == 0) {
	                *cursorY = (*cursorY - 1 + size) % size;
	                HAL_Delay(200);
	            }
				else if (entradaDireita == 0) {
	                *cursorX = (*cursorX + 1) % size;
	                HAL_Delay(200);
	            } else if (entradaEsquerda == 0) {
	                *cursorX = (*cursorX - 1 + size) % size;
	                HAL_Delay(200);
	            }

			int x_antigo = cursorX_antigo * 55 + 30;
			int y_antigo = cursorY_antigo * 50 + 25;
			ST7789_DrawFilledRectangle(x_antigo, y_antigo, 25, 5, BLACK);

        	int x = *cursorX * 55 + 30;  // Posição X
            int y = *cursorY * 50 + 25;  // Posição Y
            ST7789_DrawFilledRectangle(x, y, 25, 5, MAGENTA);
            cursorX_antigo = *cursorX;
            cursorY_antigo = *cursorY;
}

void IniciarJogo(char tabuleiro[size][size]) {
	gerarPares(tabuleiro);

	    for (int i = 0; i < size; i++){
	        for (int j = 0; j < size; j++){
	            revelado[i][j] = true;
	        }
	    }

	    desenharTabuleiro();
	    HAL_Delay(2000);

 	    for (int i = 0; i < size; i++){
	        for (int j = 0; j < size; j++){
	            revelado[i][j] = false;
	        }
	    }

	    desenharTabuleiro();

	    verifica = 1;
	}
void gerarPares(char tabuleiro[size][size]){
	char cartas[16] = {
			'Y', 'Y', 'O', 'O',
			'U', 'U', '.', '.',
			'W', 'W', 'I', 'I',
			'N', 'N', '!', '!'
	};
	for (int linha = 15; linha > 0; linha--) {
	        coluna = rand() % (linha + 1);// limita o rand "%(linha + 1)"
	        char armazenarlinha = cartas[linha]; //armazenar linha dentro
	        cartas[linha] = cartas[coluna];
	        cartas[coluna] = armazenarlinha;

	    }
	    int preencher = 0;
	    for (int linha = 0; linha < size; linha++) {
	        for (int coluna = 0; coluna < size; coluna++) {
	            tabuleiro[linha][coluna] = cartas[preencher++]; /* Atrela valor da Variavel em Froma de matriz; ex: a[3][4] = 12 */
	        }
	    }
	    verifica = 1;
}
void desenharTabuleiro() {
    for (int linha = 0; linha < size; linha++) {
        for (int coluna = 0; coluna < size; coluna++) {
            int Xletra = coluna * 55 + 34; // ajuste para centralizar a letra
            int Yletra = linha * 50 + 32;

            if (revelado[linha][coluna]) {
                char letra[2] = {tabuleiro[linha][coluna], '\0'};
                ST7789_WriteString(Xletra, Yletra, letra, Font_16x26, BLUE, colorBG);
            } else {
                // Desenha uma carta "virada" (preenchida)

                ST7789_DrawImage(coluna * 55 + 30, linha * 50 + 30, 25, 30, cartaPI);

            }
        }
    }
}
void selecionarCartas(bool revelado[size][size], int *cursorX, int *cursorY, int* cartaX, int* cartaY) {

	if (revelado[*cursorY][*cursorX] == true) {
	HAL_Delay(1000);
	ST7789_WriteString(28, 220, "                   ", Font_11x18, colorCard, colorCard);
	return;
	}
	if (selecionadas == 0) {
        *cartaX = *cursorX;
        *cartaY = *cursorY;
        revelado[*cartaY][*cartaX] = true;
       desenharTabuleiro();
        selecionadas++;

    }
	else if (selecionadas == 1) {
        carta2X = *cursorX;
        carta2Y = *cursorY;
        if (carta1X == carta2X && carta1Y == carta2Y) {
            ST7789_WriteString(28, 220, "SELECAO INVALIDA", Font_11x18, YELLOW, colorCard);
            HAL_Delay(1000);
            ST7789_WriteString(28, 220, "                ", Font_11x18, colorCard, colorCard);
            return;
        }

        revelado[carta2Y][carta2X] = true;
        desenharTabuleiro();
        HAL_Delay(1000);
        if (comparar(carta1X, carta1Y, carta2X, carta2Y)) {
            ST7789_WriteString(80, 220, "ACERTOU!", Font_11x18, GREEN, colorCard);
            HAL_Delay(1000);

        } else {
            revelado[carta1Y][carta1X] = false;
            revelado[carta2Y][carta2X] = false;
            ST7789_WriteString(80, 220, "ERROU!", Font_11x18, RED, colorCard);
            HAL_Delay(1000);

        }
        ST7789_WriteString(80, 220, "         ", Font_11x18, colorCard, colorCard);
        HAL_Delay(1000);
        desenharTabuleiro();
        selecionadas = 0;
        tentativaf();

    }

}

bool comparar(int carta1X, int carta1Y, int carta2X, int carta2Y){
	if (tabuleiro[carta1Y][carta1X] == tabuleiro[carta2Y][carta2X]){
		return true;
	}
	else{
	return false;
	}
}
void menu(){

	ST7789_Fill_Color(BLACK);
	ST7789_DrawImage(32, 29, 31, 45, New_Piskel_1_png);
	ST7789_DrawImage(22, 36, 31, 45, New_Piskel_1_png);
	ST7789_WriteString(83,45, "MEMORY", Font_16x26, WHITE, colorCard );
	ST7789_WriteString(70,65, "CARD GAME", Font_16x26, WHITE, colorCard );
	ST7789_WriteString(60, 120, "Start Game:", Font_11x18, WHITE, colorCard );
	ST7789_WriteString(32, 145, "Press PA10 Button", Font_11x18, WHITE, colorCard );
	atualizarecorde();
	tentativa = 0;
	while(HAL_GPIO_ReadPin(GPIOA, GPIO_PIN_10)==1);

}

void fimdeJogo(){
		ST7789_Fill_Color(BLACK);
		ST7789_WriteString(35,30, "CONGRATULATIONS!", Font_11x18, GREEN, BLACK);
		ST7789_WriteString(40,185, pt ,Font_11x18, YELLOW, BLACK);

		ST7789_DrawFilledRectangle(25, 80, 25, 30, MAGENTA);
		ST7789_WriteString(30,83, "Y", Font_16x26, WHITE, MAGENTA);
		ST7789_DrawFilledRectangle(25, 130, 25, 30, BLUE);
		ST7789_WriteString(30,132, "W", Font_16x26, WHITE, BLUE);

		ST7789_DrawFilledRectangle(80, 80, 25, 30, GREEN);
		ST7789_WriteString(85,83, "O", Font_16x26, WHITE, GREEN);
		ST7789_DrawFilledRectangle(80, 130, 25, 30, YELLOW);
		ST7789_WriteString(85,132, "I", Font_16x26, WHITE, YELLOW);

		ST7789_DrawFilledRectangle(135, 80, 25, 30, RED);
		ST7789_WriteString(140,83, "U", Font_16x26, WHITE, RED);
		ST7789_DrawFilledRectangle(135, 130, 25, 30, CYAN);
		ST7789_WriteString(140,132, "N", Font_16x26, WHITE, CYAN);

		ST7789_DrawFilledRectangle(190, 80, 25, 30, BRRED);
		ST7789_WriteString(195,83, ".", Font_16x26, WHITE, BRRED);
		ST7789_DrawFilledRectangle(190, 130, 25, 30, BRED);
		ST7789_WriteString(194,132, "!", Font_16x26, WHITE, BRED);
}

/* USER CODE END 4 */

void Error_Handler(void)
{
  __disable_irq();
  while (1)
  {
  }
}

/************************ (C) COPYRIGHT STMicroelectronics *****END OF FILE****/
